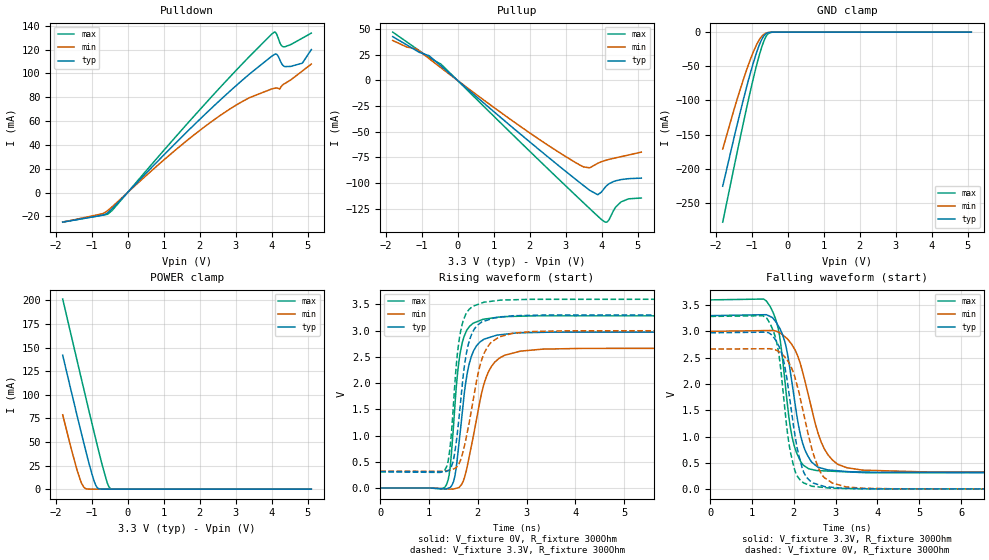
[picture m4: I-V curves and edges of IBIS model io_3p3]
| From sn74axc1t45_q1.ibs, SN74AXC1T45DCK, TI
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|   io_3p3 Model
[Model]   io_3p3
Model_type   I/O
Polarity   Non-Inverting
Enable   Active-High
Vinl = 0.8
Vinh = 2.3
Vmeas = 1.65
Vref = 0
Cref = 2pF
Rref = 100000
|   typ   min   max
C_comp   2.71423E-12   2.21642E-12   2.96238E-12
|C_comp_pullup   2.53315E-12   1.95732E-12   2.79024E-12
|C_comp_pulldown   2.47536E-12   1.83507E-12   2.75193E-12
| Where Nom  PVT is Nominal Process, 3.3V, 27C
|   Fast PVT is Strong Process,  3.6V, -40C
|   Slow PVT is Weak Process,   3.0V, 130C
[Voltage Range]   3.3   3   3.6
|Junction Temperature
[Temperature Range]   27   130   -40
[Pullup Reference]   3.3   3   3.6
[Pulldown Reference]   -0   0   0
[Power Clamp Reference]   3.3   3   3.6
[GND Clamp Reference]   0   0   0
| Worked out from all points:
|   slope of the pulldown table from 0 to 0.495 V, typ, clamps not added: 31.6 ohm
|   slope of the pullup table from 0 to 0.495 V, typ, clamps not added: 32.9 ohm
|   GND clamp passes 1 mA (typ) near -0.55 V on its own axis
|   POWER clamp passes 1 mA (typ) near -0.83 V on its own axis
|   falling waveform, V_fixture 3.3V, R_fixture 300Ohm: 20-80 % time 382ps typ, 554ps min, 313ps max; typ from 3.3 V to 0.314 V
|   rising waveform, V_fixture 0V, R_fixture 300Ohm: 20-80 % time 245ps typ, 372ps min, 191ps max; typ from 0 V to 2.97 V
|   rising waveform, V_fixture 3.3V, R_fixture 300Ohm: 20-80 % time 234ps typ, 348ps min, 187ps max; typ from 0.314 V to 3.3 V
|   falling waveform, V_fixture 0V, R_fixture 300Ohm: 20-80 % time 362ps typ, 502ps min, 302ps max; typ from 2.97 V to 0 V
[Pulldown]
|   Voltage   I(typ)   I(min)   I(max)
-1.8V     -24.81mA   -24.84mA   -24.64mA
-689.1mV  -18.94mA   -17.68mA   -18.95mA
-433.8mV  -13.67mA   -12.08mA   -15.19mA
1.07V     33.51mA    29.04mA    37.66mA
2.326V    70.74mA    59.47mA    80.25mA
3.292V    97.1mA     78.2mA     111.4mA
4.072V    115.9mA    87.49mA    134.7mA
4.141V    116mA      87.75mA    132.8mA
4.224V    111.6mA    86.84mA    126mA
4.341V    106.1mA    91.16mA    122.3mA
4.852V    108.7mA    102.1mA    129.6mA
5.1V      120mA      107.9mA    133.9mA
[GND Clamp]
|   Voltage   I(typ)   I(min)   I(max)
-1.8V     -225.8mA   -171.3mA   -278.4mA
-1.49V    -155.5mA   -114.1mA   -198.8mA
-1.372V   -129.7mA   -93.65mA   -169.2mA
-1.151V   -83.4mA    -57.67mA   -114.7mA
-944.4mV  -44.09mA   -28.45mA   -66.55mA
-820.2mV  -23.96mA   -14.47mA   -40.63mA
-716.7mV  -10.8mA    -6.208mA   -22.03mA
-613.2mV  -2.993mA   -1.853mA   -7.989mA
-523.5mV  -651.8uA   -509.8uA   -1.82mA
-420mV    -139.4uA   -116.2uA   -245.3uA
-68.1mV   -463.1nA   -631.9nA   -390.1nA
5.1V      0A         0A         0A
[Pullup]
|   Voltage   I(typ)   I(min)   I(max)
-1.8V     42.67mA    38.94mA    47.11mA
-1.145V   29.06mA    30.71mA    31.01mA
-792.6mV  24.11mA    21.33mA    22.44mA
-468.3mV  14.32mA    12.54mA    16.13mA
1.74V     -52.19mA   -44.73mA   -60.06mA
3.375V    -99.09mA   -82.07mA   -115.2mA
3.665V    -107mA     -85.15mA   -124.9mA
3.886V    -111.3mA   -80.89mA   -132.1mA
4.079V    -104.9mA   -78.2mA    -137.8mA
4.162V    -101.9mA   -77.37mA   -137.6mA
4.541V    -96.63mA   -74.26mA   -118.3mA
5.1V      -95.21mA   -69.89mA   -114.6mA
[POWER Clamp]
|   Voltage   I(typ)   I(min)   I(max)
-1.8V     141.9mA    78.74mA    201.4mA
-1.565V   104.1mA    43.12mA    163mA
-1.407V   78.83mA    20.87mA    137.2mA
-1.296V   61.5mA     8.016mA    119.2mA
-1.214V   48.71mA    2.066mA    105.8mA
-985.8mV  15.65mA    4.506uA    69.3mA
-868.5mV  3.093mA    445.5nA    50.79mA
-771.9mV  146.4uA    307.7nA    35.85mA
-571.8mV  169.2nA    292.3nA    7.669mA
-516.6mV  109.8nA    290.1nA    2.383mA
-468.3mV  101.8nA    288.5nA    390.4uA
5.1V      0A         0A         0A
[Ramp]
R_load = 300
|   typ   min   max
dV/dt_r   1.7844/2.44198e-10   1.59862/3.706e-10   1.97113/1.91271e-10
dV/dt_f   1.79187/3.81522e-10   1.60756/5.51427e-10   1.97476/3.1219e-10
[Falling Waveform]
V_fixture = 3.3V
V_fixture_min = 3V
V_fixture_max = 3.6V
R_fixture = 300Ohm
C_fixture = 0F
|   Time   V(typ)   V(min)   V(max)
0s        3.3V       3V         3.6V
1.431ns   3.286V     3.017V     3.479V
1.66ns    3.062V     2.977V     2.908V
1.833ns   2.635V     2.868V     1.705V
2.008ns   1.738V     2.676V     827.5mV
2.206ns   884.7mV    2.238V     476.1mV
2.547ns   435.5mV    1.152V     353.9mV
2.922ns   358.9mV    556mV      340.9mV
3.644ns   326.6mV    362.1mV    315.8mV
30ns      313.6mV    320.7mV    308.7mV
[Rising Waveform]
V_fixture = 0V
V_fixture_min = 0V
V_fixture_max = 0V
R_fixture = 300Ohm
C_fixture = 0F
|   Time   V(typ)   V(min)   V(max)
0s        44.53nV    100.7nV    19.95nV
1.323ns   -17.04mV   -13.98mV   12.09mV
1.431ns   7.473mV    -19.23mV   375.5mV
1.525ns   205.5mV    -13.8mV    1.492V
1.614ns   855.9mV    9.664mV    2.421V
1.719ns   1.774V     180.7mV    2.889V
1.867ns   2.506V     798.4mV    3.11V
2.14ns    2.84V      2.024V     3.22V
2.493ns   2.924V     2.501V     3.264V
30ns      2.974V     2.664V     3.285V
[Rising Waveform]
V_fixture = 3.3V
V_fixture_min = 3V
V_fixture_max = 3.6V
R_fixture = 300Ohm
C_fixture = 0F
|   Time   V(typ)   V(min)   V(max)
0s        313.6mV    320.7mV    308.7mV
1.314ns   312mV      323.7mV    326.2mV
1.405ns   339.6mV    334.1mV    587.4mV
1.513ns   599.1mV    367.5mV    1.769V
1.605ns   1.259V     449.1mV    2.747V
1.709ns   2.215V     740.5mV    3.214V
1.846ns   2.864V     1.364V     3.424V
2.08ns    3.163V     2.447V     3.525V
2.467ns   3.256V     2.886V     3.581V
30ns      3.3V       3V         3.6V
[Falling Waveform]
|Gnd
V_fixture = 0V
V_fixture_min = 0V
V_fixture_max = 0V
R_fixture = 300Ohm
C_fixture = 0F
|   Time   V(typ)   V(min)   V(max)
0s        2.974V     2.664V     3.285V
1.435ns   2.954V     2.67V      3.144V
1.614ns   2.761V     2.627V     2.698V
1.75ns    2.461V     2.543V     1.792V
2.005ns   1.13V      2.182V     402.9mV
2.206ns   386.4mV    1.54V      136.7mV
2.436ns   133.5mV    750.1mV    55.32mV
2.725ns   51.54mV    222.4mV    31.56mV
3.644ns   9.998mV    17.89mV    5.13mV
30ns      -114.4nV   285.1nV    -72.96nV
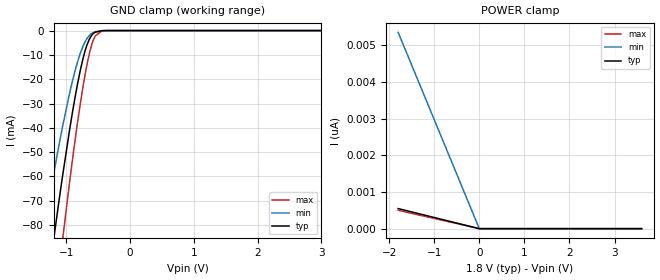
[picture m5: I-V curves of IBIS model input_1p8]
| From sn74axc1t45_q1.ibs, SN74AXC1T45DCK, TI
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|   input_1p8 Model
[Model]   input_1p8
Model_type   Input
Vinl = 0.7
Vinh = 1.6
|   typ   min   max
C_comp   1.392pf   0.843pf   1.994pF
| Where Nom  PVT is Nominal Process, 1.8V,  27C
|   Fast PVT is Strong Process,  1.98V, -40C
|   Slow PVT is Weak Process,   1.62V, 130C
[Voltage Range]   1.8   1.62   1.98
|Junction Temperature
[Temperature Range]   27   130   -40
[Power Clamp Reference]   1.8   1.62   1.98
[GND Clamp Reference]   0   0   0
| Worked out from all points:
|   GND clamp passes 1 mA (typ) near -0.56 V on its own axis
[GND Clamp]
|   Voltage   I(typ)   I(min)   I(max)
-1.8V     -210.9mA   -157.9mA   -261.6mA
-1.319V   -109.8mA   -77.26mA   -146mA
-1.206V   -87.46mA   -60.12mA   -119.6mA
-1.12V    -71.04mA   -47.78mA   -99.81mA
-1.066V   -61.14mA   -40.45mA   -87.72mA
-952.2mV  -41.52mA   -26.26mA   -63.25mA
-903.6mV  -33.72mA   -20.8mA    -53.27mA
-779.4mV  -16.26mA   -9.28mA    -30.01mA
-676.8mV  -6.025mA   -3.331mA   -14.19mA
-579.6mV  -1.299mA   -846.1uA   -4.132mA
-385.2mV  -10.15uA   -16.94uA   -26.09uA
3.6V      0A         0A         0A
[POWER Clamp]
|   Voltage   I(typ)   I(min)   I(max)
-1.8V     546.7pA    5.348nA    499.5pA
0V        0A         0A         0A
3.6V      0A         0A         0A
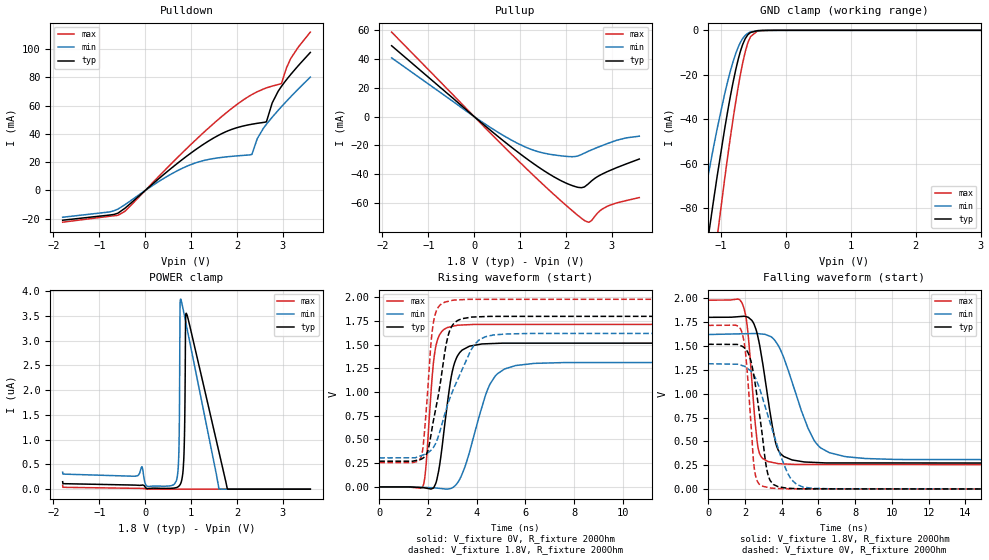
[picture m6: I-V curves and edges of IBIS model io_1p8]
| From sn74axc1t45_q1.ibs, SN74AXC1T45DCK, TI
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|   io_1p8 Model
[Model]   io_1p8
Model_type   I/O
Polarity   Non-Inverting
Enable   Active-High
Vinl = 0.7
Vinh = 1.6
Vmeas = 0.9
Vref = 0
Cref = 2pF
Rref = 100000
|   typ   min   max
C_comp   2.397pF   1.720pF   2.908pF
| Where Nom  PVT is Nominal Process, 1.8V,  27C
|   Fast PVT is Strong Process,  1.98V, -40C
|   Slow PVT is Weak Process,   1.62V, 130C
[Voltage Range]   1.8   1.62   1.98
|Junction Temperature
[Temperature Range]   27   130   -40
[Pullup Reference]   1.8   1.62   1.98
[Pulldown Reference]   0   0   0
[Power Clamp Reference]   1.8   1.62   1.98
[GND Clamp Reference]   0   0   0
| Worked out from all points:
|   slope of the pulldown table from 0 to 0.27 V, typ, clamps not added: 35.5 ohm
|   slope of the pullup table from 0 to 0.27 V, typ, clamps not added: 37.2 ohm
|   GND clamp passes 1 mA (typ) near -0.55 V on its own axis
|   falling waveform, V_fixture 1.8V, R_fixture 200Ohm: 20-80 % time 763ps typ, 1.46ns min, 443ps max; typ from 1.8 V to 0.271 V
|   rising waveform, V_fixture 0V, R_fixture 200Ohm: 20-80 % time 477ps typ, 905ps min, 299ps max; typ from 0 V to 1.52 V
|   rising waveform, V_fixture 1.8V, R_fixture 200Ohm: 20-80 % time 599ps typ, 1.14ns min, 308ps max; typ from 0.271 V to 1.8 V
|   falling waveform, V_fixture 0V, R_fixture 200Ohm: 20-80 % time 647ps typ, 1.31ns min, 386ps max; typ from 1.52 V to 0 V
[Pulldown]
|   Voltage   I(typ)   I(min)   I(max)
-1.8V     -21mA      -18.9mA    -22.39mA
-779.4mV  -17.36mA   -15.16mA   -18.21mA
-444.6mV  -12.6mA    -10.09mA   -14.76mA
981mV     26.07mA    18.09mA    32.03mA
1.683V    40.36mA    23.42mA    52.61mA
2.326V    46.8mA     25.45mA    67.73mA
2.444V    47.44mA    36.71mA    69.76mA
2.639V    48.42mA    46.61mA    72.39mA
2.768V    61.8mA     51.75mA    73.73mA
2.968V    73.4mA     59.07mA    75.46mA
3.173V    81.96mA    66.19mA    93.2mA
3.6V      97.49mA    80.06mA    111.9mA
[GND Clamp]
|   Voltage   I(typ)   I(min)   I(max)
-1.8V     -225.8mA   -171.3mA   -278.4mA
-1.314V   -117.2mA   -83.81mA   -154.6mA
-1.211V   -95.65mA   -67.06mA   -129.2mA
-1.114V   -75.96mA   -52.03mA   -105.7mA
-1.06V    -65.43mA   -44.11mA   -92.95mA
-898.2mV  -36.2mA    -22.84mA   -56.54mA
-774mV    -17.55mA   -10.32mA   -31.92mA
-671.4mV  -6.631mA   -3.831mA   -15.15mA
-579.6mV  -1.736mA   -1.163mA   -4.946mA
-444.6mV  -190.3uA   -161.6uA   -378.2uA
-347.4mV  -61.92uA   -47.58uA   -87.83uA
3.6V      0A         0A         0A
[Pullup]
|   Voltage   I(typ)   I(min)   I(max)
-1.8V     49.18mA    40.76mA    58.67mA
160.2mV   -4.328mA   -3.485mA   -5.206mA
975.6mV   -25.24mA   -19.03mA   -31.11mA
1.375V    -34.46mA   -24.18mA   -43.33mA
1.759V    -42.18mA   -26.69mA   -54.65mA
2.169V    -48.24mA   -27.81mA   -66.17mA
2.407V    -48.75mA   -25.33mA   -72.19mA
2.493V    -46.59mA   -24.03mA   -73.32mA
2.558V    -44.71mA   -23.12mA   -72.25mA
2.736V    -40.82mA   -20.8mA    -65.53mA
2.914V    -38.04mA   -18.61mA   -62.07mA
3.6V      -29.47mA   -13.6mA    -56.22mA
[POWER Clamp]
|   Voltage   I(typ)   I(min)   I(max)
-1.8V     150.6nA    343.5nA    76.87nA
635.4mV   22.8nA     101.1nA    0A
732.6mV   59.82nA    713.3nA    0A
748.8mV   75.98nA    1.843uA    0A
759.6mV   90.45nA    3.742uA    0A
770.4mV   109.1nA    3.841uA    0A
846mV     728.9nA    3.547uA    0A
878.4mV   3.332uA    3.398uA    0A
894.6mV   3.555uA    3.324uA    0A
1.607V    753.8nA    7.251nA    0A
1.791V    2.015nA    0A         0A
3.6V      0A         0A         0A
[Ramp]
R_load = 200
|   typ   min   max
dV/dt_r   0.910583/4.76876e-10   0.788176/9.03483e-10   1.02928/2.97916e-10
dV/dt_f   0.917407/7.59187e-10   0.78841/1.45112e-09   1.03442/4.43086e-10
[Falling Waveform]
V_fixture = 1.8V
V_fixture_min = 1.62V
V_fixture_max = 1.98V
R_fixture = 200Ohm
C_fixture = 0F
|   Time   V(typ)   V(min)   V(max)
0s        1.8V       1.62V      1.98V
1.858ns   1.81V      1.628V     1.943V
2.147ns   1.802V     1.629V     1.67V
2.699ns   1.603V     1.629V     452.4mV
3.252ns   953mV      1.61V      289.7mV
3.665ns   491.9mV    1.549V     273.6mV
3.961ns   367.8mV    1.449V     265.9mV
5.445ns   282.9mV    635.4mV    258.7mV
6.594ns   274.7mV    382.7mV    258.7mV
30ns      271mV      306mV      256mV
[Rising Waveform]
V_fixture = 0V
V_fixture_min = 0V
V_fixture_max = 0V
R_fixture = 200Ohm
C_fixture = 0F
|   Time   V(typ)   V(min)   V(max)
0s        61.67nV    261.3nV    -82.44nV
1.782ns   -7.99mV    -4.588mV   -737.1uV
1.924ns   -12.97mV   -6.038mV   234.6mV
2.238ns   -7.833mV   -9.239mV   1.337V
2.556ns   372.4mV    -17.72mV   1.635V
2.93ns    1.121V     -17.28mV   1.688V
3.217ns   1.383V     45.36mV    1.705V
4.551ns   1.51V      1.086V     1.713V
6.374ns   1.515V     1.302V     1.713V
50ns      1.518V     1.314V     1.715V
[Rising Waveform]
V_fixture = 1.8V
V_fixture_min = 1.62V
V_fixture_max = 1.98V
R_fixture = 200Ohm
C_fixture = 0F
|   Time   V(typ)   V(min)   V(max)
0s        271mV      306mV      256mV
1.71ns    290.7mV    328.7mV    309.2mV
1.995ns   381.9mV    360.8mV    1.038V
2.147ns   584.4mV    393.2mV    1.576V
2.265ns   751.9mV    433.8mV    1.786V
2.756ns   1.515V     824.3mV    1.952V
3.067ns   1.723V     1.043V     1.97V
4.069ns   1.793V     1.542V     1.977V
5.227ns   1.798V     1.612V     1.977V
50ns      1.8V       1.62V      1.98V
[Falling Waveform]
|Gnd
V_fixture = 0V
V_fixture_min = 0V
V_fixture_max = 0V
R_fixture = 200Ohm
C_fixture = 0F
|   Time   V(typ)   V(min)   V(max)
0s        1.518V     1.314V     1.715V
1.799ns   1.501V     1.298V     1.663V
2.06ns    1.461V     1.276V     1.375V
2.527ns   1.144V     1.18V      196mV
2.984ns   504.5mV    939.5mV    29.8mV
3.23ns    172.9mV    784.4mV    19.53mV
3.541ns   49.78mV    591.8mV    9.779mV
4.372ns   9.106mV    151mV      2.909mV
5.192ns   3.07mV     21.39mV    2.905mV
30ns      -57.54nV   452.8nV    -94.86nV
